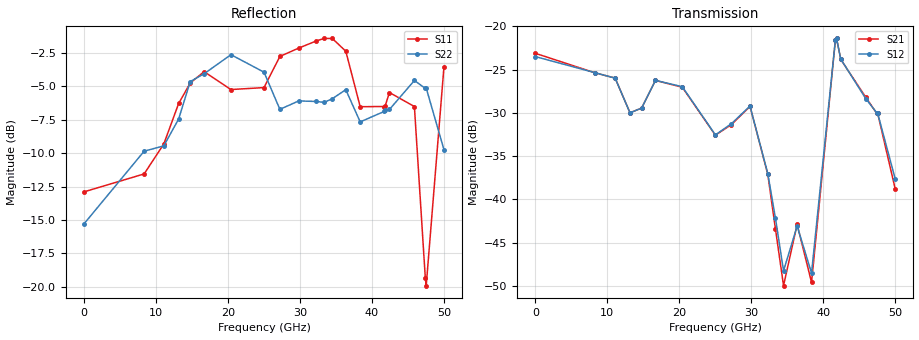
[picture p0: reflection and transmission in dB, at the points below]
!Keysight Technologies,N5245B,MY58422270,A.16.20.02
!Date: Thursday, March 05, 2026 01:28:01
!Correction: S11(C  2-Port  )
!S21(C  2-Port  )
!S12(C  2-Port  )
!S22(C  2-Port  )
!S2P File: Measurements: S11, S21, S12, S22:
# Hz S  dB  R 50
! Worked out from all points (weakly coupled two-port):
!   3201 points, 10 MHz to 50 GHz, reference 50 ohm
!   highest |S21| = -21.39 dB at 41.83 GHz (marker M1); lowest = -50.0 dB at 34.47 GHz (marker M2)
!   lowest |S11| = -19.9 dB at 47.53 GHz (marker M3), VSWR 1.22, Z = 45.9 + j8.84 ohm
!   |S11| at or under -10 dB: start of sweep to 10.09 GHz; 11.36 GHz to 11.92 GHz (560.3 MHz wide, 4.81 % of centre); 46.66 GHz to 48.28 GHz (1.628 GHz wide, 3.43 % of centre)
!   |S22| runs from -19.8 to -2.6 dB; largest |S21 - S12| = 0.0031
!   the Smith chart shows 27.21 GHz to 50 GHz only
!   S11 on the Smith chart (normalised r, x): 27.21 GHz: 0.18, +0.36; 32.28 GHz: 0.42, +1.84; 36.36 GHz: 2.41, -3.36; 42.42 GHz: 1.01, -1.27; 47.41 GHz: 0.84, +0.12; 50 GHz: 0.61, -1.35
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1e7  -12.89 -3.9  -23.12 3.0  -23.50 2.2  -15.28 39.7
8.352081e9  -11.55 175.0  -25.39 29.5  -25.37 29.6  -9.85 -173.0
1.108591e10  -9.31 109.2  -25.98 -73.1  -25.99 -73.4  -9.45 85.0
1.3148e10  -6.28 64.7  -29.99 -131.3  -29.99 -131.3  -7.44 -22.7
1.475705e10  -4.75 13.3  -29.44 -152.5  -29.45 -152.9  -4.64 -90.4
1.667854e10  -3.90 -43.8  -26.25 157.9  -26.24 157.7  -4.06 -140.9
2.041217e10  -5.24 -121.7  -27.04 39.0  -26.98 39.4  -2.63 155.1
2.5005e10  -5.09 179.7  -32.58 -66.2  -32.54 -65.9  -3.94 71.6
2.720768e10  -2.76 139.2  -31.37 -114.6  -31.27 -115.5  -6.72 32.1
2.981654e10  -2.14 94.0  -29.26 159.9  -29.21 159.8  -6.09 -28.3
3.228479e10  -1.60 55.1  -37.11 46.7  -37.02 48.6  -6.13 -103.1
3.334708e10  -1.42 36.0  -43.41 5.4  -42.16 4.1  -6.20 -126.5
3.447186e10  -1.41 15.9  -49.97 -103.5  -48.25 -106.4  -5.93 -150.3
3.63621e10  -2.37 -22.7  -42.88 118.5  -43.08 111.5  -5.25 174.2
3.83617e10  -6.52 -22.2  -49.59 -97.6  -48.51 -99.3  -7.66 141.5
4.167354e10  -6.51 -52.6  -21.60 -54.5  -21.57 -55.3  -6.88 115.4
4.182976e10  -6.47 -52.6  -21.39 -69.1  -21.39 -69.6  -6.76 113.9
4.242339e10  -5.46 -57.3  -23.83 -114.3  -23.79 -114.5  -6.73 110.0
4.589145e10  -6.51 -117.3  -28.19 50.4  -28.35 50.6  -4.56 62.5
4.740677e10  -19.34 138.6  -30.05 -0.2  -29.98 -0.7  -5.15 43.0
4.753174e10  -19.91 109.5  -30.00 -2.3  -30.00 -2.2  -5.13 41.7
5e10  -3.52 -66.1  -38.85 -130.7  -37.69 -137.8  -9.74 4.3
